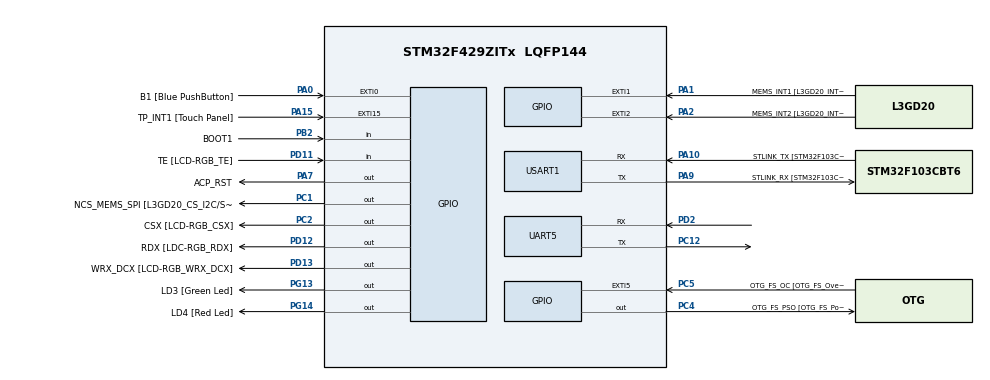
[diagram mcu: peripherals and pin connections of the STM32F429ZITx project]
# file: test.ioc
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Mcu.Family=STM32F4
Mcu.Name=STM32F429ZITx
Mcu.Package=LQFP144
NVIC.PriorityGroup=NVIC_PRIORITYGROUP_0
PA0/WKUP.GPIO_Label=B1 [Blue PushButton]
PA0/WKUP.GPIO_ModeDefaultEXTI=GPIO_MODE_EVT_RISING
PA0/WKUP.GPIO_PuPd=GPIO_NOPULL
PA0/WKUP.Signal=GPXTI0
PA1.GPIO_Label=MEMS_INT1 [L3GD20_INT1]
PA1.GPIO_ModeDefaultEXTI=GPIO_MODE_EVT_RISING
PA1.GPIO_PuPd=GPIO_NOPULL
PA1.Signal=GPXTI1
PA10.GPIO_Label=STLINK_TX [STM32F103CBT6_PA2]
PA10.Mode=Asynchronous
PA10.Signal=USART1_RX
PA11.GPIO_Label=R4
PA11.GPIO_Mode=GPIO_MODE_AF_PP
PA11.GPIO_PuPd=GPIO_NOPULL
PA11.GPIO_Speed=GPIO_SPEED_FREQ_LOW
PA11.Signal=LTDC_R4
PA12.GPIO_Label=R5
PA12.GPIO_Mode=GPIO_MODE_AF_PP
PA12.GPIO_PuPd=GPIO_NOPULL
PA12.GPIO_Speed=GPIO_SPEED_FREQ_LOW
PA12.Signal=LTDC_R5
PA13.GPIO_Label=SWDIO
PA13.Signal=SYS_JTMS-SWDIO
PA14.GPIO_Label=SWCLK
PA14.Signal=SYS_JTCK-SWCLK
PA15.GPIO_Label=TP_INT1 [Touch Panel]
PA15.GPIO_ModeDefaultEXTI=GPIO_MODE_EVT_RISING
PA15.GPIO_PuPd=GPIO_NOPULL
PA15.Signal=GPXTI15
PA2.GPIO_Label=MEMS_INT2 [L3GD20_INT2]
PA2.GPIO_ModeDefaultEXTI=GPIO_MODE_EVT_RISING
PA2.GPIO_PuPd=GPIO_NOPULL
PA2.Signal=GPXTI2
PA3.GPIO_Label=B5
PA3.GPIO_Mode=GPIO_MODE_AF_PP
PA3.GPIO_PuPd=GPIO_NOPULL
PA3.GPIO_Speed=GPIO_SPEED_FREQ_LOW
PA3.Signal=LTDC_B5
PA4.GPIO_Label=VSYNC
PA4.GPIO_Mode=GPIO_MODE_AF_PP
PA4.GPIO_PuPd=GPIO_NOPULL
PA4.GPIO_Speed=GPIO_SPEED_FREQ_LOW
PA4.Signal=LTDC_VSYNC
PA6.GPIO_Label=G2
PA6.GPIO_Mode=GPIO_MODE_AF_PP
PA6.GPIO_PuPd=GPIO_NOPULL
PA6.GPIO_Speed=GPIO_SPEED_FREQ_LOW
PA6.Signal=LTDC_G2
PA7.GPIO_Label=ACP_RST
PA7.GPIO_Mode=GPIO_MODE_OUTPUT_PP
PA7.GPIO_PuPd=GPIO_NOPULL
PA7.GPIO_Speed=GPIO_SPEED_FREQ_LOW
PA7.Signal=GPIO_Output
PA8.GPIO_Label=I2C3_SCL [ACP/RF_SCL]
PA8.GPIO_Mode=GPIO_MODE_AF_OD
PA8.GPIO_PuPd=GPIO_NOPULL
PA8.GPIO_Speed=GPIO_SPEED_FREQ_LOW
PA8.Signal=I2C3_SCL
PA9.GPIO_Label=STLINK_RX [STM32F103CBT6_PA3]
PA9.Mode=Asynchronous
PA9.Signal=USART1_TX
PB0.GPIO_Label=R3
PB0.GPIO_Mode=GPIO_MODE_AF_PP
PB0.GPIO_PuPd=GPIO_NOPULL
PB0.GPIO_Speed=GPIO_SPEED_FREQ_LOW
PB0.Signal=LTDC_R3
PB1.GPIO_Label=R6
PB1.GPIO_Mode=GPIO_MODE_AF_PP
PB1.GPIO_PuPd=GPIO_NOPULL
PB1.GPIO_Speed=GPIO_SPEED_FREQ_LOW
PB1.Signal=LTDC_R6
PB10.GPIO_Label=G4
PB10.GPIO_Mode=GPIO_MODE_AF_PP
PB10.GPIO_PuPd=GPIO_NOPULL
PB10.GPIO_Speed=GPIO_SPEED_FREQ_LOW
PB10.Signal=LTDC_G4
PB11.GPIO_Label=G5
PB11.GPIO_Mode=GPIO_MODE_AF_PP
PB11.GPIO_PuPd=GPIO_NOPULL
PB11.GPIO_Speed=GPIO_SPEED_FREQ_LOW
PB11.Signal=LTDC_G5
PB12.GPIO_Label=OTG_HS_ID
PB12.GPIO_Mode=GPIO_MODE_AF_PP
PB12.GPIO_PuPd=GPIO_NOPULL
PB12.GPIO_Speed=GPIO_SPEED_FREQ_LOW
PB12.Signal=USB_OTG_HS_ID
PB13.GPIO_Label=VBUS_HS
PB13.GPIO_Mode=GPIO_MODE_INPUT
PB13.GPIO_PuPd=GPIO_NOPULL
PB13.Signal=USB_OTG_HS_VBUS
PB14.GPIO_Label=OTG_HS_DM
PB14.GPIO_Mode=GPIO_MODE_AF_PP
PB14.GPIO_PuPd=GPIO_NOPULL
PB14.GPIO_Speed=GPIO_SPEED_FREQ_LOW
PB14.Signal=USB_OTG_HS_DM
PB15.GPIO_Label=OTG_HS_DP
PB15.GPIO_Mode=GPIO_MODE_AF_PP
PB15.GPIO_PuPd=GPIO_NOPULL
PB15.GPIO_Speed=GPIO_SPEED_FREQ_LOW
PB15.Signal=USB_OTG_HS_DP
PB2/BOOT1.GPIO_Label=BOOT1
PB2/BOOT1.GPIO_Mode=GPIO_MODE_INPUT
PB2/BOOT1.GPIO_PuPd=GPIO_NOPULL
PB2/BOOT1.Signal=GPIO_Input
PB5.GPIO_Label=SDCKE1
PB5.GPIO_Mode=GPIO_MODE_AF_PP
PB5.GPIO_PuPd=GPIO_NOPULL
PB5.GPIO_Speed=GPIO_SPEED_FREQ_VERY_HIGH
PB5.Signal=FMC_SDCKE1
PB6.GPIO_Label=SDNE1 [SDRAM_CS]
PB6.GPIO_Mode=GPIO_MODE_AF_PP
PB6.GPIO_PuPd=GPIO_NOPULL
PB6.GPIO_Speed=GPIO_SPEED_FREQ_VERY_HIGH
PB6.Signal=FMC_SDNE1
PB8.GPIO_Label=B6
PB8.GPIO_Mode=GPIO_MODE_AF_PP
PB8.GPIO_PuPd=GPIO_NOPULL
PB8.GPIO_Speed=GPIO_SPEED_FREQ_LOW
PB8.Signal=LTDC_B6
PB9.GPIO_Label=B7
PB9.GPIO_Mode=GPIO_MODE_AF_PP
PB9.GPIO_PuPd=GPIO_NOPULL
PB9.GPIO_Speed=GPIO_SPEED_FREQ_LOW
PB9.Signal=LTDC_B7
PC0.GPIO_Label=SDNWE
PC0.GPIO_Mode=GPIO_MODE_AF_PP
PC0.GPIO_PuPd=GPIO_NOPULL
PC0.GPIO_Speed=GPIO_SPEED_FREQ_VERY_HIGH
PC0.Signal=FMC_SDNWE
PC1.GPIO_Label=NCS_MEMS_SPI [L3GD20_CS_I2C/SPI]
PC1.GPIO_Mode=GPIO_MODE_OUTPUT_PP
PC1.GPIO_PuPd=GPIO_NOPULL
PC1.GPIO_Speed=GPIO_SPEED_FREQ_LOW
PC1.Signal=GPIO_Output
PC10.GPIO_Label=R2
PC10.GPIO_Mode=GPIO_MODE_AF_PP
PC10.GPIO_PuPd=GPIO_NOPULL
PC10.GPIO_Speed=GPIO_SPEED_FREQ_LOW
PC10.Signal=LTDC_R2
PC12.Mode=Asynchronous
PC12.Signal=UART5_TX
PC14/OSC32_IN.GPIO_Label=PC14-OSC32_IN
PC14/OSC32_IN.Signal=RCC_OSC32_IN
PC15/OSC32_OUT.GPIO_Label=PC15-OSC32_OUT
PC15/OSC32_OUT.Signal=RCC_OSC32_OUT
PC2.GPIO_Label=CSX [LCD-RGB_CSX]
PC2.GPIO_Mode=GPIO_MODE_OUTPUT_PP
PC2.GPIO_PuPd=GPIO_NOPULL
PC2.GPIO_Speed=GPIO_SPEED_FREQ_LOW
PC2.Signal=GPIO_Output
PC4.GPIO_Label=OTG_FS_PSO [OTG_FS_PowerSwitchOn]
PC4.GPIO_Mode=GPIO_MODE_OUTPUT_PP
PC4.GPIO_PuPd=GPIO_NOPULL
PC4.GPIO_Speed=GPIO_SPEED_FREQ_LOW
PC4.Signal=GPIO_Output
PC5.GPIO_Label=OTG_FS_OC [OTG_FS_OverCurrent]
PC5.GPIO_ModeDefaultEXTI=GPIO_MODE_EVT_RISING
PC5.Signal=GPXTI5
PC6.GPIO_Label=HSYNC
PC6.GPIO_Mode=GPIO_MODE_AF_PP
PC6.GPIO_PuPd=GPIO_NOPULL
PC6.GPIO_Speed=GPIO_SPEED_FREQ_LOW
PC6.Signal=LTDC_HSYNC
PC7.GPIO_Label=G6
PC7.GPIO_Mode=GPIO_MODE_AF_PP
PC7.GPIO_PuPd=GPIO_NOPULL
PC7.GPIO_Speed=GPIO_SPEED_FREQ_LOW
PC7.Signal=LTDC_G6
PC9.GPIO_Label=I2C3_SDA [ACP/RF_SDA]
PC9.GPIO_Mode=GPIO_MODE_AF_OD
PC9.GPIO_PuPd=GPIO_NOPULL
PC9.GPIO_Speed=GPIO_SPEED_FREQ_LOW
PC9.Signal=I2C3_SDA
PD0.GPIO_Label=D2
PD0.GPIO_Mode=GPIO_MODE_AF_PP
PD0.GPIO_PuPd=GPIO_NOPULL
PD0.GPIO_Speed=GPIO_SPEED_FREQ_VERY_HIGH
PD0.Signal=FMC_D2_DA2
PD1.GPIO_Label=D3
PD1.GPIO_Mode=GPIO_MODE_AF_PP
PD1.GPIO_PuPd=GPIO_NOPULL
PD1.GPIO_Speed=GPIO_SPEED_FREQ_VERY_HIGH
PD1.Signal=FMC_D3_DA3
PD10.GPIO_Label=D15
PD10.GPIO_Mode=GPIO_MODE_AF_PP
PD10.GPIO_PuPd=GPIO_NOPULL
PD10.GPIO_Speed=GPIO_SPEED_FREQ_VERY_HIGH
PD10.Signal=FMC_D15_DA15
PD11.GPIO_Label=TE [LCD-RGB_TE]
PD11.GPIO_Mode=GPIO_MODE_INPUT
PD11.GPIO_PuPd=GPIO_NOPULL
PD11.Signal=GPIO_Input
PD12.GPIO_Label=RDX [LDC-RGB_RDX]
PD12.GPIO_Mode=GPIO_MODE_OUTPUT_PP
PD12.GPIO_PuPd=GPIO_NOPULL
PD12.GPIO_Speed=GPIO_SPEED_FREQ_LOW
PD12.Signal=GPIO_Output
PD13.GPIO_Label=WRX_DCX [LCD-RGB_WRX_DCX]
PD13.GPIO_Mode=GPIO_MODE_OUTPUT_PP
PD13.GPIO_PuPd=GPIO_NOPULL
PD13.GPIO_Speed=GPIO_SPEED_FREQ_LOW
PD13.Signal=GPIO_Output
PD14.GPIO_Label=D0
PD14.GPIO_Mode=GPIO_MODE_AF_PP
PD14.GPIO_PuPd=GPIO_NOPULL
PD14.GPIO_Speed=GPIO_SPEED_FREQ_VERY_HIGH
PD14.Signal=FMC_D0_DA0
PD15.GPIO_Label=D1
PD15.GPIO_Mode=GPIO_MODE_AF_PP
PD15.GPIO_PuPd=GPIO_NOPULL
PD15.GPIO_Speed=GPIO_SPEED_FREQ_VERY_HIGH
PD15.Signal=FMC_D1_DA1
PD2.Mode=Asynchronous
PD2.Signal=UART5_RX
PD3.GPIO_Label=G7
PD3.GPIO_Mode=GPIO_MODE_AF_PP
PD3.GPIO_PuPd=GPIO_NOPULL
PD3.GPIO_Speed=GPIO_SPEED_FREQ_LOW
PD3.Signal=LTDC_G7
PD6.GPIO_Label=B2
PD6.GPIO_Mode=GPIO_MODE_AF_PP
PD6.GPIO_PuPd=GPIO_NOPULL
PD6.GPIO_Speed=GPIO_SPEED_FREQ_LOW
PD6.Signal=LTDC_B2
PD8.GPIO_Label=D13
PD8.GPIO_Mode=GPIO_MODE_AF_PP
PD8.GPIO_PuPd=GPIO_NOPULL
PD8.GPIO_Speed=GPIO_SPEED_FREQ_VERY_HIGH
PD8.Signal=FMC_D13_DA13
PD9.GPIO_Label=D14
PD9.GPIO_Mode=GPIO_MODE_AF_PP
PD9.GPIO_PuPd=GPIO_NOPULL
PD9.GPIO_Speed=GPIO_SPEED_FREQ_VERY_HIGH
PD9.Signal=FMC_D14_DA14
PE0.GPIO_Label=NBL0 [SDRAM_LDQM]
PE0.GPIO_Mode=GPIO_MODE_AF_PP
PE0.GPIO_PuPd=GPIO_NOPULL
PE0.GPIO_Speed=GPIO_SPEED_FREQ_VERY_HIGH
PE0.Signal=FMC_NBL0
PE1.GPIO_Label=NBL1 [SDRAM_UDQM]
PE1.GPIO_Mode=GPIO_MODE_AF_PP
PE1.GPIO_PuPd=GPIO_NOPULL
PE1.GPIO_Speed=GPIO_SPEED_FREQ_VERY_HIGH
PE1.Signal=FMC_NBL1
PE10.GPIO_Label=D7
PE10.GPIO_Mode=GPIO_MODE_AF_PP
PE10.GPIO_PuPd=GPIO_NOPULL
PE10.GPIO_Speed=GPIO_SPEED_FREQ_VERY_HIGH
PE10.Signal=FMC_D7_DA7
PE11.GPIO_Label=D8
PE11.GPIO_Mode=GPIO_MODE_AF_PP
PE11.GPIO_PuPd=GPIO_NOPULL
PE11.GPIO_Speed=GPIO_SPEED_FREQ_VERY_HIGH
PE11.Signal=FMC_D8_DA8
PE12.GPIO_Label=D9
PE12.GPIO_Mode=GPIO_MODE_AF_PP
PE12.GPIO_PuPd=GPIO_NOPULL
PE12.GPIO_Speed=GPIO_SPEED_FREQ_VERY_HIGH
PE12.Signal=FMC_D9_DA9
PE13.GPIO_Label=D10
PE13.GPIO_Mode=GPIO_MODE_AF_PP
PE13.GPIO_PuPd=GPIO_NOPULL
PE13.GPIO_Speed=GPIO_SPEED_FREQ_VERY_HIGH
PE13.Signal=FMC_D10_DA10
PE14.GPIO_Label=D11
PE14.GPIO_Mode=GPIO_MODE_AF_PP
PE14.GPIO_PuPd=GPIO_NOPULL
PE14.GPIO_Speed=GPIO_SPEED_FREQ_VERY_HIGH
PE14.Signal=FMC_D11_DA11
PE15.GPIO_Label=D12
PE15.GPIO_Mode=GPIO_MODE_AF_PP
PE15.GPIO_PuPd=GPIO_NOPULL
PE15.GPIO_Speed=GPIO_SPEED_FREQ_VERY_HIGH
PE15.Signal=FMC_D12_DA12
PE7.GPIO_Label=D4
PE7.GPIO_Mode=GPIO_MODE_AF_PP
PE7.GPIO_PuPd=GPIO_NOPULL
PE7.GPIO_Speed=GPIO_SPEED_FREQ_VERY_HIGH
PE7.Signal=FMC_D4_DA4
PE8.GPIO_Label=D5
PE8.GPIO_Mode=GPIO_MODE_AF_PP
PE8.GPIO_PuPd=GPIO_NOPULL
PE8.GPIO_Speed=GPIO_SPEED_FREQ_VERY_HIGH
PE8.Signal=FMC_D5_DA5
PE9.GPIO_Label=D6
PE9.GPIO_Mode=GPIO_MODE_AF_PP
PE9.GPIO_PuPd=GPIO_NOPULL
PE9.GPIO_Speed=GPIO_SPEED_FREQ_VERY_HIGH
PE9.Signal=FMC_D6_DA6
PF0.GPIO_Label=A0
PF0.GPIO_Mode=GPIO_MODE_AF_PP
PF0.GPIO_PuPd=GPIO_NOPULL
PF0.GPIO_Speed=GPIO_SPEED_FREQ_VERY_HIGH
PF0.Signal=FMC_A0
PF1.GPIO_Label=A1
PF1.GPIO_Mode=GPIO_MODE_AF_PP
PF1.GPIO_PuPd=GPIO_NOPULL
PF1.GPIO_Speed=GPIO_SPEED_FREQ_VERY_HIGH
PF1.Signal=FMC_A1
PF10.GPIO_Label=ENABLE [LCD-RGB_ENABLE]
PF10.GPIO_Mode=GPIO_MODE_AF_PP
PF10.GPIO_PuPd=GPIO_NOPULL
PF10.GPIO_Speed=GPIO_SPEED_FREQ_LOW
PF10.Signal=LTDC_DE
PF11.GPIO_Label=SDNRAS
PF11.GPIO_Mode=GPIO_MODE_AF_PP
PF11.GPIO_PuPd=GPIO_NOPULL
PF11.GPIO_Speed=GPIO_SPEED_FREQ_VERY_HIGH
PF11.Signal=FMC_SDNRAS
PF12.GPIO_Label=A6
PF12.GPIO_Mode=GPIO_MODE_AF_PP
PF12.GPIO_PuPd=GPIO_NOPULL
PF12.GPIO_Speed=GPIO_SPEED_FREQ_VERY_HIGH
PF12.Signal=FMC_A6
PF13.GPIO_Label=A7
PF13.GPIO_Mode=GPIO_MODE_AF_PP
PF13.GPIO_PuPd=GPIO_NOPULL
PF13.GPIO_Speed=GPIO_SPEED_FREQ_VERY_HIGH
PF13.Signal=FMC_A7
PF14.GPIO_Label=A8
PF14.GPIO_Mode=GPIO_MODE_AF_PP
PF14.GPIO_PuPd=GPIO_NOPULL
PF14.GPIO_Speed=GPIO_SPEED_FREQ_VERY_HIGH
PF14.Signal=FMC_A8
PF15.GPIO_Label=A9
PF15.GPIO_Mode=GPIO_MODE_AF_PP
PF15.GPIO_PuPd=GPIO_NOPULL
PF15.GPIO_Speed=GPIO_SPEED_FREQ_VERY_HIGH
PF15.Signal=FMC_A9
PF2.GPIO_Label=A2
PF2.GPIO_Mode=GPIO_MODE_AF_PP
PF2.GPIO_PuPd=GPIO_NOPULL
PF2.GPIO_Speed=GPIO_SPEED_FREQ_VERY_HIGH
PF2.Signal=FMC_A2
PF3.GPIO_Label=A3
PF3.GPIO_Mode=GPIO_MODE_AF_PP
PF3.GPIO_PuPd=GPIO_NOPULL
PF3.GPIO_Speed=GPIO_SPEED_FREQ_VERY_HIGH
PF3.Signal=FMC_A3
PF4.GPIO_Label=A4
PF4.GPIO_Mode=GPIO_MODE_AF_PP
PF4.GPIO_PuPd=GPIO_NOPULL
PF4.GPIO_Speed=GPIO_SPEED_FREQ_VERY_HIGH
PF4.Signal=FMC_A4
PF5.GPIO_Label=A5
PF5.GPIO_Mode=GPIO_MODE_AF_PP
PF5.GPIO_PuPd=GPIO_NOPULL
PF5.GPIO_Speed=GPIO_SPEED_FREQ_VERY_HIGH
PF5.Signal=FMC_A5
PF7.GPIO_Label=SPI5_SCK [L3GD20_SCL/SPC]
PF7.GPIO_Mode=GPIO_MODE_AF_PP
PF7.GPIO_PuPd=GPIO_NOPULL
PF7.GPIO_Speed=GPIO_SPEED_FREQ_LOW
PF7.Signal=SPI5_SCK
PF8.GPIO_Label=SPI5_MISO [L3GD20_SDO]
PF8.GPIO_Mode=GPIO_MODE_AF_PP
PF8.GPIO_PuPd=GPIO_NOPULL
PF8.GPIO_Speed=GPIO_SPEED_FREQ_LOW
PF8.Signal=SPI5_MISO
PF9.GPIO_Label=SPI5_MOSI [L3GD20_SDA/SDI/SDO]
PF9.GPIO_Mode=GPIO_MODE_AF_PP
PF9.GPIO_PuPd=GPIO_NOPULL
PF9.GPIO_Speed=GPIO_SPEED_FREQ_LOW
PF9.Signal=SPI5_MOSI
PG0.GPIO_Label=A10
PG0.GPIO_Mode=GPIO_MODE_AF_PP
PG0.GPIO_PuPd=GPIO_NOPULL
PG0.GPIO_Speed=GPIO_SPEED_FREQ_VERY_HIGH
PG0.Signal=FMC_A10
PG1.GPIO_Label=A11
PG1.GPIO_Mode=GPIO_MODE_AF_PP
PG1.GPIO_PuPd=GPIO_NOPULL
PG1.GPIO_Speed=GPIO_SPEED_FREQ_VERY_HIGH
PG1.Signal=FMC_A11
PG10.GPIO_Label=G3
PG10.GPIO_Mode=GPIO_MODE_AF_PP
PG10.GPIO_PuPd=GPIO_NOPULL
PG10.GPIO_Speed=GPIO_SPEED_FREQ_LOW
PG10.Signal=LTDC_G3
PG11.GPIO_Label=B3
PG11.GPIO_Mode=GPIO_MODE_AF_PP
PG11.GPIO_PuPd=GPIO_NOPULL
PG11.GPIO_Speed=GPIO_SPEED_FREQ_LOW
PG11.Signal=LTDC_B3
PG12.GPIO_Label=B4
PG12.GPIO_Mode=GPIO_MODE_AF_PP
PG12.GPIO_PuPd=GPIO_NOPULL
PG12.GPIO_Speed=GPIO_SPEED_FREQ_LOW
PG12.Signal=LTDC_B4
PG13.GPIO_Label=LD3 [Green Led]
PG13.GPIO_Mode=GPIO_MODE_OUTPUT_PP
PG13.GPIO_PuPd=GPIO_NOPULL
PG13.GPIO_Speed=GPIO_SPEED_FREQ_LOW
PG13.Signal=GPIO_Output
PG14.GPIO_Label=LD4 [Red Led]
PG14.GPIO_Mode=GPIO_MODE_OUTPUT_PP
PG14.GPIO_PuPd=GPIO_NOPULL
PG14.GPIO_Speed=GPIO_SPEED_FREQ_LOW
PG14.Signal=GPIO_Output
PG15.GPIO_Label=SDNCAS
PG15.GPIO_Mode=GPIO_MODE_AF_PP
PG15.GPIO_PuPd=GPIO_NOPULL
PG15.GPIO_Speed=GPIO_SPEED_FREQ_VERY_HIGH
PG15.Signal=FMC_SDNCAS
PG4.GPIO_Label=BA0
PG4.GPIO_Mode=GPIO_MODE_AF_PP
PG4.GPIO_PuPd=GPIO_NOPULL
PG4.GPIO_Speed=GPIO_SPEED_FREQ_VERY_HIGH
PG4.Signal=FMC_A14_BA0
PG5.GPIO_Label=BA1
PG5.GPIO_Mode=GPIO_MODE_AF_PP
PG5.GPIO_PuPd=GPIO_NOPULL
PG5.GPIO_Speed=GPIO_SPEED_FREQ_VERY_HIGH
PG5.Signal=FMC_A15_BA1
PG6.GPIO_Label=R7
PG6.GPIO_Mode=GPIO_MODE_AF_PP
PG6.GPIO_PuPd=GPIO_NOPULL
PG6.GPIO_Speed=GPIO_SPEED_FREQ_LOW
PG6.Signal=LTDC_R7
PG7.GPIO_Label=DOTCLK [LCT-RGB_DOTCLK]
PG7.GPIO_Mode=GPIO_MODE_AF_PP
PG7.GPIO_PuPd=GPIO_NOPULL
PG7.GPIO_Speed=GPIO_SPEED_FREQ_LOW
PG7.Signal=LTDC_CLK
PG8.GPIO_Label=SDCLK
PG8.GPIO_Mode=GPIO_MODE_AF_PP
PG8.GPIO_PuPd=GPIO_NOPULL
PG8.GPIO_Speed=GPIO_SPEED_FREQ_VERY_HIGH
PG8.Signal=FMC_SDCLK
PH0/OSC_IN.GPIO_Label=PH0-OSC_IN
PH0/OSC_IN.Signal=RCC_OSC_IN
PH1/OSC_OUT.GPIO_Label=PH1-OSC_OUT
PH1/OSC_OUT.Signal=RCC_OSC_OUT
ProjectManager.HeapSize=0x200
ProjectManager.StackSize=0x400
ProjectManager.TargetToolchain=STM32CubeIDE
RCC.48MHZClocksFreq_Value=14285714.285714285
RCC.AHBFreq_Value=16000000
RCC.APB1CLKDivider=RCC_HCLK_DIV8
RCC.APB1Freq_Value=2000000
RCC.APB1TimFreq_Value=4000000
RCC.APB2CLKDivider=RCC_HCLK_DIV4
RCC.APB2Freq_Value=4000000
RCC.APB2TimFreq_Value=8000000
RCC.CortexFreq_Value=16000000
RCC.HCLKFreq_Value=16000000
RCC.HSE_VALUE=8000000
RCC.HSI_VALUE=16000000
RCC.LSE_VALUE=32768
RCC.PLLM=8
RCC.PLLN=50
RCC.PLLP=RCC_PLLP_DIV4
RCC.PLLQ=7
RCC.SYSCLKFreq_VALUE=16000000
RCC.VCOOutputFreq_Value=100000000
SH.FMC_A0.0=FMC_A0
SH.FMC_A1.0=FMC_A1
SH.FMC_A10.0=FMC_A10
SH.FMC_A11.0=FMC_A11
SH.FMC_A14_BA0.0=FMC_BA0
SH.FMC_A15_BA1.0=FMC_BA1
SH.FMC_A2.0=FMC_A2
SH.FMC_A3.0=FMC_A3
SH.FMC_A4.0=FMC_A4
SH.FMC_A5.0=FMC_A5
SH.FMC_A6.0=FMC_A6
SH.FMC_A7.0=FMC_A7
SH.FMC_A8.0=FMC_A8
SH.FMC_A9.0=FMC_A9
SH.FMC_D0_DA0.0=FMC_D0
SH.FMC_D10_DA10.0=FMC_D10
SH.FMC_D11_DA11.0=FMC_D11
SH.FMC_D12_DA12.0=FMC_D12
SH.FMC_D13_DA13.0=FMC_D13
SH.FMC_D14_DA14.0=FMC_D14
SH.FMC_D15_DA15.0=FMC_D15
SH.FMC_D1_DA1.0=FMC_D1
SH.FMC_D2_DA2.0=FMC_D2
SH.FMC_D3_DA3.0=FMC_D3
SH.FMC_D4_DA4.0=FMC_D4
SH.FMC_D5_DA5.0=FMC_D5
SH.FMC_D6_DA6.0=FMC_D6
SH.FMC_D7_DA7.0=FMC_D7
SH.FMC_D8_DA8.0=FMC_D8
SH.FMC_D9_DA9.0=FMC_D9
SH.FMC_NBL0.0=FMC_NBL0
SH.FMC_NBL1.0=FMC_NBL1
SH.FMC_SDCLK.0=FMC_SDCLK
SH.FMC_SDNCAS.0=FMC_SDNCAS
SH.FMC_SDNRAS.0=FMC_SDNRAS
SH.FMC_SDNWE.0=FMC_SDNWE
UART5.VirtualMode=Asynchronous
USART1.VirtualMode=VM_ASYNC
board=STM32F429I-DISC1

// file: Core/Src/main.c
/* USER CODE BEGIN Header */
/**
  ******************************************************************************
  * @file           : main.c
  * @brief          : Main program body
  ******************************************************************************
  * @attention
  *
  * Copyright (c) 2023 STMicroelectronics.
  * All rights reserved.
  *
  * This software is licensed under terms that can be found in the LICENSE file
  * in the root directory of this software component.
  * If no LICENSE file comes with this software, it is provided AS-IS.
  *
  ******************************************************************************
  */
/* USER CODE END Header */
#include "main.h"

UART_HandleTypeDef huart5;
UART_HandleTypeDef huart1;

void SystemClock_Config(void);
static void MX_GPIO_Init(void);
static void MX_USART1_UART_Init(void);
static void MX_UART5_Init(void);

int main(void)
{

  /* MCU Configuration--------------------------------------------------------*/

  /* Reset of all peripherals, Initializes the Flash interface and the Systick. */
  HAL_Init();

  /* Configure the system clock */
  SystemClock_Config();

  /* Initialize all configured peripherals */
  MX_GPIO_Init();
  MX_USART1_UART_Init();
  MX_UART5_Init();

  /* Infinite loop */
  while (1)
  {

  }
}

void SystemClock_Config(void)
{
  RCC_OscInitTypeDef RCC_OscInitStruct = {0};
  RCC_ClkInitTypeDef RCC_ClkInitStruct = {0};

  /** Configure the main internal regulator output voltage
  */
  __HAL_RCC_PWR_CLK_ENABLE();
  __HAL_PWR_VOLTAGESCALING_CONFIG(PWR_REGULATOR_VOLTAGE_SCALE3);

  /** Initializes the RCC Oscillators according to the specified parameters
  * in the RCC_OscInitTypeDef structure.
  */
  RCC_OscInitStruct.OscillatorType = RCC_OSCILLATORTYPE_HSI;
  RCC_OscInitStruct.HSIState = RCC_HSI_ON;
  RCC_OscInitStruct.HSICalibrationValue = RCC_HSICALIBRATION_DEFAULT;
  RCC_OscInitStruct.PLL.PLLState = RCC_PLL_ON;
  RCC_OscInitStruct.PLL.PLLSource = RCC_PLLSOURCE_HSI;
  RCC_OscInitStruct.PLL.PLLM = 8;
  RCC_OscInitStruct.PLL.PLLN = 50;
  RCC_OscInitStruct.PLL.PLLP = RCC_PLLP_DIV4;
  RCC_OscInitStruct.PLL.PLLQ = 7;
  if (HAL_RCC_OscConfig(&RCC_OscInitStruct) != HAL_OK)
  {
    Error_Handler();
  }

  /** Initializes the CPU, AHB and APB buses clocks
  */
  RCC_ClkInitStruct.ClockType = RCC_CLOCKTYPE_HCLK|RCC_CLOCKTYPE_SYSCLK
                              |RCC_CLOCKTYPE_PCLK1|RCC_CLOCKTYPE_PCLK2;
  RCC_ClkInitStruct.SYSCLKSource = RCC_SYSCLKSOURCE_PLLCLK;
  RCC_ClkInitStruct.AHBCLKDivider = RCC_SYSCLK_DIV1;
  RCC_ClkInitStruct.APB1CLKDivider = RCC_HCLK_DIV8;
  RCC_ClkInitStruct.APB2CLKDivider = RCC_HCLK_DIV4;

  if (HAL_RCC_ClockConfig(&RCC_ClkInitStruct, FLASH_LATENCY_0) != HAL_OK)
  {
    Error_Handler();
  }
}

static void MX_UART5_Init(void)
{

  huart5.Instance = UART5;
  huart5.Init.BaudRate = 115200;
  huart5.Init.WordLength = UART_WORDLENGTH_8B;
  huart5.Init.StopBits = UART_STOPBITS_1;
  huart5.Init.Parity = UART_PARITY_NONE;
  huart5.Init.Mode = UART_MODE_TX_RX;
  huart5.Init.HwFlowCtl = UART_HWCONTROL_NONE;
  huart5.Init.OverSampling = UART_OVERSAMPLING_16;
  if (HAL_UART_Init(&huart5) != HAL_OK)
  {
    Error_Handler();
  }

}

static void MX_USART1_UART_Init(void)
{

  huart1.Instance = USART1;
  huart1.Init.BaudRate = 115200;
  huart1.Init.WordLength = UART_WORDLENGTH_8B;
  huart1.Init.StopBits = UART_STOPBITS_1;
  huart1.Init.Parity = UART_PARITY_NONE;
  huart1.Init.Mode = UART_MODE_TX_RX;
  huart1.Init.HwFlowCtl = UART_HWCONTROL_NONE;
  huart1.Init.OverSampling = UART_OVERSAMPLING_16;
  if (HAL_UART_Init(&huart1) != HAL_OK)
  {
    Error_Handler();
  }

}

static void MX_GPIO_Init(void)
{
  GPIO_InitTypeDef GPIO_InitStruct = {0};

  /* GPIO Ports Clock Enable */
  __HAL_RCC_GPIOC_CLK_ENABLE();
  __HAL_RCC_GPIOF_CLK_ENABLE();
  __HAL_RCC_GPIOH_CLK_ENABLE();
  __HAL_RCC_GPIOA_CLK_ENABLE();
  __HAL_RCC_GPIOB_CLK_ENABLE();
  __HAL_RCC_GPIOG_CLK_ENABLE();
  __HAL_RCC_GPIOE_CLK_ENABLE();
  __HAL_RCC_GPIOD_CLK_ENABLE();

  /*Configure GPIO pin Output Level */
  HAL_GPIO_WritePin(GPIOC, NCS_MEMS_SPI_Pin|CSX_Pin|OTG_FS_PSO_Pin, GPIO_PIN_RESET);

  /*Configure GPIO pin Output Level */
  HAL_GPIO_WritePin(ACP_RST_GPIO_Port, ACP_RST_Pin, GPIO_PIN_RESET);

  /*Configure GPIO pin Output Level */
  HAL_GPIO_WritePin(GPIOD, RDX_Pin|WRX_DCX_Pin, GPIO_PIN_RESET);

  /*Configure GPIO pin Output Level */
  HAL_GPIO_WritePin(GPIOG, LD3_Pin|LD4_Pin, GPIO_PIN_RESET);

  /*Configure GPIO pins : A0_Pin A1_Pin A2_Pin A3_Pin
                           A4_Pin A5_Pin SDNRAS_Pin A6_Pin
                           A7_Pin A8_Pin A9_Pin */
  GPIO_InitStruct.Pin = A0_Pin|A1_Pin|A2_Pin|A3_Pin
                          |A4_Pin|A5_Pin|SDNRAS_Pin|A6_Pin
                          |A7_Pin|A8_Pin|A9_Pin;
  GPIO_InitStruct.Mode = GPIO_MODE_AF_PP;
  GPIO_InitStruct.Pull = GPIO_NOPULL;
  GPIO_InitStruct.Speed = GPIO_SPEED_FREQ_VERY_HIGH;
  GPIO_InitStruct.Alternate = GPIO_AF12_FMC;
  HAL_GPIO_Init(GPIOF, &GPIO_InitStruct);

  /*Configure GPIO pins : SPI5_SCK_Pin SPI5_MISO_Pin SPI5_MOSI_Pin */
  GPIO_InitStruct.Pin = SPI5_SCK_Pin|SPI5_MISO_Pin|SPI5_MOSI_Pin;
  GPIO_InitStruct.Mode = GPIO_MODE_AF_PP;
  GPIO_InitStruct.Pull = GPIO_NOPULL;
  GPIO_InitStruct.Speed = GPIO_SPEED_FREQ_LOW;
  GPIO_InitStruct.Alternate = GPIO_AF5_SPI5;
  HAL_GPIO_Init(GPIOF, &GPIO_InitStruct);

  /*Configure GPIO pin : ENABLE_Pin */
  GPIO_InitStruct.Pin = ENABLE_Pin;
  GPIO_InitStruct.Mode = GPIO_MODE_AF_PP;
  GPIO_InitStruct.Pull = GPIO_NOPULL;
  GPIO_InitStruct.Speed = GPIO_SPEED_FREQ_LOW;
  GPIO_InitStruct.Alternate = GPIO_AF14_LTDC;
  HAL_GPIO_Init(ENABLE_GPIO_Port, &GPIO_InitStruct);

  /*Configure GPIO pin : SDNWE_Pin */
  GPIO_InitStruct.Pin = SDNWE_Pin;
  GPIO_InitStruct.Mode = GPIO_MODE_AF_PP;
  GPIO_InitStruct.Pull = GPIO_NOPULL;
  GPIO_InitStruct.Speed = GPIO_SPEED_FREQ_VERY_HIGH;
  GPIO_InitStruct.Alternate = GPIO_AF12_FMC;
  HAL_GPIO_Init(SDNWE_GPIO_Port, &GPIO_InitStruct);

  /*Configure GPIO pins : NCS_MEMS_SPI_Pin CSX_Pin OTG_FS_PSO_Pin */
  GPIO_InitStruct.Pin = NCS_MEMS_SPI_Pin|CSX_Pin|OTG_FS_PSO_Pin;
  GPIO_InitStruct.Mode = GPIO_MODE_OUTPUT_PP;
  GPIO_InitStruct.Pull = GPIO_NOPULL;
  GPIO_InitStruct.Speed = GPIO_SPEED_FREQ_LOW;
  HAL_GPIO_Init(GPIOC, &GPIO_InitStruct);

  /*Configure GPIO pins : B1_Pin MEMS_INT1_Pin MEMS_INT2_Pin TP_INT1_Pin */
  GPIO_InitStruct.Pin = B1_Pin|MEMS_INT1_Pin|MEMS_INT2_Pin|TP_INT1_Pin;
  GPIO_InitStruct.Mode = GPIO_MODE_EVT_RISING;
  GPIO_InitStruct.Pull = GPIO_NOPULL;
  HAL_GPIO_Init(GPIOA, &GPIO_InitStruct);

  /*Configure GPIO pins : B5_Pin VSYNC_Pin G2_Pin R4_Pin
                           R5_Pin */
  GPIO_InitStruct.Pin = B5_Pin|VSYNC_Pin|G2_Pin|R4_Pin
                          |R5_Pin;
  GPIO_InitStruct.Mode = GPIO_MODE_AF_PP;
  GPIO_InitStruct.Pull = GPIO_NOPULL;
  GPIO_InitStruct.Speed = GPIO_SPEED_FREQ_LOW;
  GPIO_InitStruct.Alternate = GPIO_AF14_LTDC;
  HAL_GPIO_Init(GPIOA, &GPIO_InitStruct);

  /*Configure GPIO pin : ACP_RST_Pin */
  GPIO_InitStruct.Pin = ACP_RST_Pin;
  GPIO_InitStruct.Mode = GPIO_MODE_OUTPUT_PP;
  GPIO_InitStruct.Pull = GPIO_NOPULL;
  GPIO_InitStruct.Speed = GPIO_SPEED_FREQ_LOW;
  HAL_GPIO_Init(ACP_RST_GPIO_Port, &GPIO_InitStruct);

  /*Configure GPIO pin : OTG_FS_OC_Pin */
  GPIO_InitStruct.Pin = OTG_FS_OC_Pin;
  GPIO_InitStruct.Mode = GPIO_MODE_EVT_RISING;
  GPIO_InitStruct.Pull = GPIO_NOPULL;
  HAL_GPIO_Init(OTG_FS_OC_GPIO_Port, &GPIO_InitStruct);

  /*Configure GPIO pins : R3_Pin R6_Pin */
  GPIO_InitStruct.Pin = R3_Pin|R6_Pin;
  GPIO_InitStruct.Mode = GPIO_MODE_AF_PP;
  GPIO_InitStruct.Pull = GPIO_NOPULL;
  GPIO_InitStruct.Speed = GPIO_SPEED_FREQ_LOW;
  GPIO_InitStruct.Alternate = GPIO_AF9_LTDC;
  HAL_GPIO_Init(GPIOB, &GPIO_InitStruct);

  /*Configure GPIO pin : BOOT1_Pin */
  GPIO_InitStruct.Pin = BOOT1_Pin;
  GPIO_InitStruct.Mode = GPIO_MODE_INPUT;
  GPIO_InitStruct.Pull = GPIO_NOPULL;
  HAL_GPIO_Init(BOOT1_GPIO_Port, &GPIO_InitStruct);

  /*Configure GPIO pins : A10_Pin A11_Pin BA0_Pin BA1_Pin
                           SDCLK_Pin SDNCAS_Pin */
  GPIO_InitStruct.Pin = A10_Pin|A11_Pin|BA0_Pin|BA1_Pin
                          |SDCLK_Pin|SDNCAS_Pin;
  GPIO_InitStruct.Mode = GPIO_MODE_AF_PP;
  GPIO_InitStruct.Pull = GPIO_NOPULL;
  GPIO_InitStruct.Speed = GPIO_SPEED_FREQ_VERY_HIGH;
  GPIO_InitStruct.Alternate = GPIO_AF12_FMC;
  HAL_GPIO_Init(GPIOG, &GPIO_InitStruct);

  /*Configure GPIO pins : D4_Pin D5_Pin D6_Pin D7_Pin
                           D8_Pin D9_Pin D10_Pin D11_Pin
                           D12_Pin NBL0_Pin NBL1_Pin */
  GPIO_InitStruct.Pin = D4_Pin|D5_Pin|D6_Pin|D7_Pin
                          |D8_Pin|D9_Pin|D10_Pin|D11_Pin
                          |D12_Pin|NBL0_Pin|NBL1_Pin;
  GPIO_InitStruct.Mode = GPIO_MODE_AF_PP;
  GPIO_InitStruct.Pull = GPIO_NOPULL;
  GPIO_InitStruct.Speed = GPIO_SPEED_FREQ_VERY_HIGH;
  GPIO_InitStruct.Alternate = GPIO_AF12_FMC;
  HAL_GPIO_Init(GPIOE, &GPIO_InitStruct);

  /*Configure GPIO pins : G4_Pin G5_Pin B6_Pin B7_Pin */
  GPIO_InitStruct.Pin = G4_Pin|G5_Pin|B6_Pin|B7_Pin;
  GPIO_InitStruct.Mode = GPIO_MODE_AF_PP;
  GPIO_InitStruct.Pull = GPIO_NOPULL;
  GPIO_InitStruct.Speed = GPIO_SPEED_FREQ_LOW;
  GPIO_InitStruct.Alternate = GPIO_AF14_LTDC;
  HAL_GPIO_Init(GPIOB, &GPIO_InitStruct);

  /*Configure GPIO pins : OTG_HS_ID_Pin OTG_HS_DM_Pin OTG_HS_DP_Pin */
  GPIO_InitStruct.Pin = OTG_HS_ID_Pin|OTG_HS_DM_Pin|OTG_HS_DP_Pin;
  GPIO_InitStruct.Mode = GPIO_MODE_AF_PP;
  GPIO_InitStruct.Pull = GPIO_NOPULL;
  GPIO_InitStruct.Speed = GPIO_SPEED_FREQ_LOW;
  GPIO_InitStruct.Alternate = GPIO_AF12_OTG_HS_FS;
  HAL_GPIO_Init(GPIOB, &GPIO_InitStruct);

  /*Configure GPIO pin : VBUS_HS_Pin */
  GPIO_InitStruct.Pin = VBUS_HS_Pin;
  GPIO_InitStruct.Mode = GPIO_MODE_INPUT;
  GPIO_InitStruct.Pull = GPIO_NOPULL;
  HAL_GPIO_Init(VBUS_HS_GPIO_Port, &GPIO_InitStruct);

  /*Configure GPIO pins : D13_Pin D14_Pin D15_Pin D0_Pin
                           D1_Pin D2_Pin D3_Pin */
  GPIO_InitStruct.Pin = D13_Pin|D14_Pin|D15_Pin|D0_Pin
                          |D1_Pin|D2_Pin|D3_Pin;
  GPIO_InitStruct.Mode = GPIO_MODE_AF_PP;
  GPIO_InitStruct.Pull = GPIO_NOPULL;
  GPIO_InitStruct.Speed = GPIO_SPEED_FREQ_VERY_HIGH;
  GPIO_InitStruct.Alternate = GPIO_AF12_FMC;
  HAL_GPIO_Init(GPIOD, &GPIO_InitStruct);

  /*Configure GPIO pin : TE_Pin */
  GPIO_InitStruct.Pin = TE_Pin;
  GPIO_InitStruct.Mode = GPIO_MODE_INPUT;
  GPIO_InitStruct.Pull = GPIO_NOPULL;
  HAL_GPIO_Init(TE_GPIO_Port, &GPIO_InitStruct);

  /*Configure GPIO pins : RDX_Pin WRX_DCX_Pin */
  GPIO_InitStruct.Pin = RDX_Pin|WRX_DCX_Pin;
  GPIO_InitStruct.Mode = GPIO_MODE_OUTPUT_PP;
  GPIO_InitStruct.Pull = GPIO_NOPULL;
  GPIO_InitStruct.Speed = GPIO_SPEED_FREQ_LOW;
  HAL_GPIO_Init(GPIOD, &GPIO_InitStruct);

  /*Configure GPIO pins : R7_Pin DOTCLK_Pin B3_Pin */
  GPIO_InitStruct.Pin = R7_Pin|DOTCLK_Pin|B3_Pin;
  GPIO_InitStruct.Mode = GPIO_MODE_AF_PP;
  GPIO_InitStruct.Pull = GPIO_NOPULL;
  GPIO_InitStruct.Speed = GPIO_SPEED_FREQ_LOW;
  GPIO_InitStruct.Alternate = GPIO_AF14_LTDC;
  HAL_GPIO_Init(GPIOG, &GPIO_InitStruct);

  /*Configure GPIO pins : HSYNC_Pin G6_Pin R2_Pin */
  GPIO_InitStruct.Pin = HSYNC_Pin|G6_Pin|R2_Pin;
  GPIO_InitStruct.Mode = GPIO_MODE_AF_PP;
  GPIO_InitStruct.Pull = GPIO_NOPULL;
  GPIO_InitStruct.Speed = GPIO_SPEED_FREQ_LOW;
  GPIO_InitStruct.Alternate = GPIO_AF14_LTDC;
  HAL_GPIO_Init(GPIOC, &GPIO_InitStruct);

  /*Configure GPIO pin : I2C3_SDA_Pin */
  GPIO_InitStruct.Pin = I2C3_SDA_Pin;
  GPIO_InitStruct.Mode = GPIO_MODE_AF_OD;
  GPIO_InitStruct.Pull = GPIO_NOPULL;
  GPIO_InitStruct.Speed = GPIO_SPEED_FREQ_LOW;
  GPIO_InitStruct.Alternate = GPIO_AF4_I2C3;
  HAL_GPIO_Init(I2C3_SDA_GPIO_Port, &GPIO_InitStruct);

  /*Configure GPIO pin : I2C3_SCL_Pin */
  GPIO_InitStruct.Pin = I2C3_SCL_Pin;
  GPIO_InitStruct.Mode = GPIO_MODE_AF_OD;
  GPIO_InitStruct.Pull = GPIO_NOPULL;
  GPIO_InitStruct.Speed = GPIO_SPEED_FREQ_LOW;
  GPIO_InitStruct.Alternate = GPIO_AF4_I2C3;
  HAL_GPIO_Init(I2C3_SCL_GPIO_Port, &GPIO_InitStruct);

  /*Configure GPIO pins : G7_Pin B2_Pin */
  GPIO_InitStruct.Pin = G7_Pin|B2_Pin;
  GPIO_InitStruct.Mode = GPIO_MODE_AF_PP;
  GPIO_InitStruct.Pull = GPIO_NOPULL;
  GPIO_InitStruct.Speed = GPIO_SPEED_FREQ_LOW;
  GPIO_InitStruct.Alternate = GPIO_AF14_LTDC;
  HAL_GPIO_Init(GPIOD, &GPIO_InitStruct);

  /*Configure GPIO pins : G3_Pin B4_Pin */
  GPIO_InitStruct.Pin = G3_Pin|B4_Pin;
  GPIO_InitStruct.Mode = GPIO_MODE_AF_PP;
  GPIO_InitStruct.Pull = GPIO_NOPULL;
  GPIO_InitStruct.Speed = GPIO_SPEED_FREQ_LOW;
  GPIO_InitStruct.Alternate = GPIO_AF9_LTDC;
  HAL_GPIO_Init(GPIOG, &GPIO_InitStruct);

  /*Configure GPIO pins : LD3_Pin LD4_Pin */
  GPIO_InitStruct.Pin = LD3_Pin|LD4_Pin;
  GPIO_InitStruct.Mode = GPIO_MODE_OUTPUT_PP;
  GPIO_InitStruct.Pull = GPIO_NOPULL;
  GPIO_InitStruct.Speed = GPIO_SPEED_FREQ_LOW;
  HAL_GPIO_Init(GPIOG, &GPIO_InitStruct);

  /*Configure GPIO pins : SDCKE1_Pin SDNE1_Pin */
  GPIO_InitStruct.Pin = SDCKE1_Pin|SDNE1_Pin;
  GPIO_InitStruct.Mode = GPIO_MODE_AF_PP;
  GPIO_InitStruct.Pull = GPIO_NOPULL;
  GPIO_InitStruct.Speed = GPIO_SPEED_FREQ_VERY_HIGH;
  GPIO_InitStruct.Alternate = GPIO_AF12_FMC;
  HAL_GPIO_Init(GPIOB, &GPIO_InitStruct);

}

void Error_Handler(void)
{
  __disable_irq();
  while (1)
  {
  }
}
